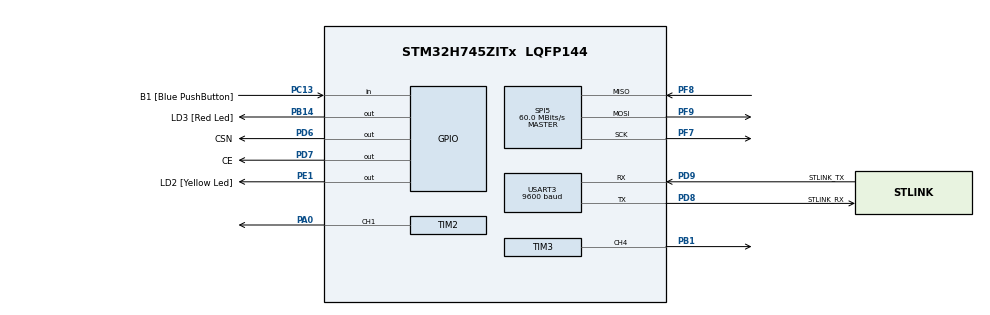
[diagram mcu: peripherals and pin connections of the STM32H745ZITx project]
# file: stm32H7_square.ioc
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CortexM4.IPs=BDMA,CORTEX_M4\:I,DEBUG,DMA,FATFS_M4\:I,FREERTOS_M4\:I,GPIO,IWDG2\:I,MDMA,NVIC2\:I,OPENAMP_M4\:I,PDM2PCM_M4\:I,PWR,RCC,RESMGR_UTILITY,SYS_M4\:I,USB_DEVICE_M4\:I,USB_HOST_M4\:I,VREFBUF,WWDG2\:I,USART3
CortexM4.Pins=PE1
CortexM7.IPs=BDMA\:I,CORTEX_M7\:I,DEBUG\:I,DMA\:I,FATFS_M7\:I,FREERTOS_M7\:I,GPIO\:I,IWDG1\:I,MDMA\:I,NVIC1\:I,OPENAMP_M7\:I,PDM2PCM_M7\:I,PWR\:I,RCC\:I,RESMGR_UTILITY\:I,SYS\:I,USB_DEVICE_M7\:I,USB_HOST_M7\:I,VREFBUF\:I,WWDG1\:I,USART3\:I,TIM2\:I,SPI5\:I,TIM3\:I
CortexM7.Pins=PC13
Mcu.Family=STM32H7
Mcu.Name=STM32H745ZITx
Mcu.Package=LQFP144
NVIC1.PriorityGroup=NVIC_PRIORITYGROUP_4
NVIC2.PriorityGroup=NVIC_PRIORITYGROUP_4
PA0.PinAttribute=CortexM7
PA0.Signal=S_TIM2_CH1_ETR
PB1.PinAttribute=CortexM7
PB1.Signal=S_TIM3_CH4
PB14.GPIO_Label=LD3 [Red Led]
PB14.PinAttribute=Free
PB14.Signal=GPIO_Output
PC12.PinAttribute=CortexM7
PC12.Signal=SPI3_MOSI
PC13.GPIO_Label=B1 [Blue PushButton]
PC13.PinAttribute=CortexM7
PC13.Signal=GPIO_Input
PC14-OSC32_IN\ (OSC32_IN).Mode=LSE-External-Oscillator
PC14-OSC32_IN\ (OSC32_IN).PinAttribute=CortexM7
PC14-OSC32_IN\ (OSC32_IN).Signal=RCC_OSC32_IN
PC15-OSC32_OUT\ (OSC32_OUT).Mode=LSE-External-Oscillator
PC15-OSC32_OUT\ (OSC32_OUT).PinAttribute=CortexM7
PC15-OSC32_OUT\ (OSC32_OUT).Signal=RCC_OSC32_OUT
PD6.GPIO_Label=CSN
PD6.PinAttribute=Free
PD6.Signal=GPIO_Output
PD7.GPIO_Label=CE
PD7.PinAttribute=Free
PD7.Signal=GPIO_Output
PD8.GPIO_Label=STLINK_RX
PD8.Mode=Asynchronous
PD8.PinAttribute=CortexM7
PD8.Signal=USART3_TX
PD9.GPIO_Label=STLINK_TX
PD9.Mode=Asynchronous
PD9.PinAttribute=CortexM7
PD9.Signal=USART3_RX
PE1.GPIO_Label=LD2 [Yellow Led]
PE1.PinAttribute=CortexM4
PE1.Signal=GPIO_Output
PF7.Mode=Full_Duplex_Master
PF7.PinAttribute=CortexM7
PF7.Signal=SPI5_SCK
PF8.Mode=Full_Duplex_Master
PF8.PinAttribute=CortexM7
PF8.Signal=SPI5_MISO
PF9.Mode=Full_Duplex_Master
PF9.PinAttribute=CortexM7
PF9.Signal=SPI5_MOSI
PH0-OSC_IN\ (PH0).Mode=HSE-External-Clock-Source
PH0-OSC_IN\ (PH0).PinAttribute=CortexM7
PH0-OSC_IN\ (PH0).Signal=RCC_OSC_IN
ProjectManager.HeapSize=M4-0x200,M7-0x200
ProjectManager.StackSize=M4-0x400,M7-0x400
ProjectManager.TargetToolchain=STM32CubeIDE
RCC.ADCFreq_Value=16125000
RCC.APB1Freq_Value=120000000
RCC.APB2Freq_Value=120000000
RCC.APB3Freq_Value=120000000
RCC.APB4Freq_Value=120000000
RCC.CortexFreq_Value=480000000
RCC.D1PPRE=RCC_APB3_DIV2
RCC.D2PPRE1=RCC_APB1_DIV2
RCC.D2PPRE2=RCC_APB2_DIV2
RCC.D3PPRE=RCC_APB4_DIV2
RCC.DIVM1=2
RCC.DIVN1=240
RCC.HCLKFreq_Value=240000000
RCC.HPRE=RCC_HCLK_DIV2
RCC.HSE_VALUE=8000000
RCC.PLLSourceVirtual=RCC_PLLSOURCE_HSE
RCC.SPI123CLockSelection=RCC_SPI123CLKSOURCE_CLKP
RCC.SYSCLKFreq_VALUE=480000000
RCC.SYSCLKSource=RCC_SYSCLKSOURCE_PLLCLK
RCC.USBFreq_Value=480000000
SH.S_TIM2_CH1_ETR.0=TIM2_CH1,PWM Generation1 CH1
SH.S_TIM3_CH4.0=TIM3_CH4,PWM Generation4 CH4
SPI5.CalculateBaudRate=60.0 MBits/s
SPI5.Direction=SPI_DIRECTION_2LINES
SPI5.Mode=SPI_MODE_MASTER
SPI5.VirtualType=VM_MASTER
TIM2.AutoReloadPreload=TIM_AUTORELOAD_PRELOAD_ENABLE
TIM2.Channel-PWM\ Generation1\ CH1=TIM_CHANNEL_1
TIM2.Period=63999
TIM2.Prescaler=74
TIM3.AutoReloadPreload=TIM_AUTORELOAD_PRELOAD_ENABLE
TIM3.Channel-PWM\ Generation4\ CH4=TIM_CHANNEL_4
TIM3.Period=63999
TIM3.Prescaler=74
USART3.BaudRate=9600
USART3.VirtualMode-Asynchronous=VM_ASYNC
VP_TIM2_VS_ClockSourceINT.Mode=Internal
VP_TIM3_VS_ClockSourceINT.Mode=Internal
board=custom

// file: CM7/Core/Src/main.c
/* USER CODE BEGIN Header */
/**
 ******************************************************************************
 * @file           : main.c
 * @brief          : Main program body
 ******************************************************************************
 * @attention
 *
 * Copyright (c) 2024 STMicroelectronics.
 * All rights reserved.
 *
 * This software is licensed under terms that can be found in the LICENSE file
 * in the root directory of this software component.
 * If no LICENSE file comes with this software, it is provided AS-IS.
 *
 ******************************************************************************
 */
/* USER CODE END Header */
#include "main.h"

/* USER CODE BEGIN Includes */
#include "MY_NRF24.h"
/* USER CODE END Includes */

/* USER CODE BEGIN PD */

#ifndef HSEM_ID_0
#define HSEM_ID_0 (0U) /* HW semaphore 0*/
#endif

#define Nrf_CE_Pin GPIO_PIN_6
#define Nrf_CE_GPIO_Port GPIOC
#define Nrf_CSn_Pin GPIO_PIN_7
#define Nrf_CSn_GPIO_Port GPIOC
/* USER CODE END PD */

SPI_HandleTypeDef hspi5;

TIM_HandleTypeDef htim2;
TIM_HandleTypeDef htim3;

UART_HandleTypeDef huart3;

void SystemClock_Config(void);
static void MX_GPIO_Init(void);
static void MX_USART3_UART_Init(void);
static void MX_TIM2_Init(void);
static void MX_SPI5_Init(void);
static void MX_TIM3_Init(void);

/* USER CODE BEGIN 0 */
uint64_t RxpipeAddrs = 0x11223344AA;
char myRxData[50];

//Control de giro servomotor ------------------------------------------------

void Rotate_Left() {
	__HAL_TIM_SET_COMPARE(&htim3, TIM_CHANNEL_4, (63999 * 0.05));
}

void Rotate_Center(void) {
	__HAL_TIM_SET_COMPARE(&htim3, TIM_CHANNEL_4, 63999 * 0.075);
}

void Rotate_Right(void) {
	__HAL_TIM_SET_COMPARE(&htim3, TIM_CHANNEL_4, (63999 * 0.1));
}

void rotate(uint32_t angle) {
	double val = (angle + 45) * 0.05 / 90 + 0.05;
	__HAL_TIM_SET_COMPARE(&htim3, TIM_CHANNEL_4, (63999 * val));
}

//-----------------------------------------------------------------------------------

//Control de potencia de traccion-----------------------------------------------------

void Forward(double power) { //POWER 50-100
	double val = 0.5f;
	uint32_t arg = 0;
	double speed = power * 0.025 / 100;
//	double speed = power * 0.05 / 100;
	HAL_Delay(2000);
	while (val * 100 < 101) { //Target : 0.1
		val = val + 0.01f;
		arg = (63999 * 0.075) + (63999 * speed * val);
//		arg = (63999 * 0.05) + (63999 * speed * val);
		__HAL_TIM_SET_COMPARE(&htim2, TIM_CHANNEL_1, arg);
		HAL_Delay(100);
	}
}

void Backward(double power) { //POWER 0-100
	double val = 0.5f;
	uint32_t arg = 0;
	double speed = power * 0.025 / 100;
	HAL_Delay(2000);
	while (val * 100 < 101) { //Target : 0.05
		val = val + 0.01f;
		arg = (63999 * 0.075) - (63999 * speed * val);
		__HAL_TIM_SET_COMPARE(&htim2, TIM_CHANNEL_1, arg);
		HAL_Delay(100);
	}
}

//----------------------------------------------------------------------------------------

void processCharacters(char *data) {
	int i = 0;
	char c;

	while ((c = data[i++]) != '\0') { // Recorre cada carácter hasta encontrar el caracter nulo '\0'
		switch (c) {
		case 'r':
			Rotate_Right();
			break;
		case 'l':
			Rotate_Left();
			break;
		case 'c':
			Rotate_Center();
			break;
		case 'f':
			Forward(70);
			break;
		case 'b':
			Backward(20);
			break;
		case '1':
			HAL_Delay(1000);
			break;
		default:
			// Opcional: Manejar caracteres no esperados o simplemente no hacer nada
			break;
		}
	}
}
/* USER CODE END 0 */

int main(void)
{
/* USER CODE BEGIN Boot_Mode_Sequence_0 */
	int32_t timeout;
/* USER CODE END Boot_Mode_Sequence_0 */

/* USER CODE BEGIN Boot_Mode_Sequence_1 */
	/* Wait until CPU2 boots and enters in stop mode or timeout*/
	timeout = 0xFFFF;
	while ((__HAL_RCC_GET_FLAG(RCC_FLAG_D2CKRDY) != RESET) && (timeout-- > 0))
		;
	if (timeout < 0) {
		Error_Handler();
	}
/* USER CODE END Boot_Mode_Sequence_1 */
  /* MCU Configuration--------------------------------------------------------*/

  /* Reset of all peripherals, Initializes the Flash interface and the Systick. */
  HAL_Init();

  /* Configure the system clock */
  SystemClock_Config();
/* USER CODE BEGIN Boot_Mode_Sequence_2 */
	/* When system initialization is finished, Cortex-M7 will release Cortex-M4 by means of
	 HSEM notification */
	/*HW semaphore Clock enable*/
	__HAL_RCC_HSEM_CLK_ENABLE();
	/*Take HSEM */
	HAL_HSEM_FastTake(HSEM_ID_0);
	/*Release HSEM in order to notify the CPU2(CM4)*/
	HAL_HSEM_Release(HSEM_ID_0, 0);
	/* wait until CPU2 wakes up from stop mode */
	timeout = 0xFFFF;
	while ((__HAL_RCC_GET_FLAG(RCC_FLAG_D2CKRDY) == RESET) && (timeout-- > 0))
		;
	if (timeout < 0) {
		Error_Handler();
	}
/* USER CODE END Boot_Mode_Sequence_2 */

  /* Initialize all configured peripherals */
  MX_GPIO_Init();
  MX_USART3_UART_Init();
  MX_TIM2_Init();
  MX_SPI5_Init();
  MX_TIM3_Init();
  /* USER CODE BEGIN 2 */
	HAL_TIM_PWM_Start(&htim2, TIM_CHANNEL_1);
	HAL_TIM_PWM_Start(&htim3, TIM_CHANNEL_4);
	//NO ACK
	NRF24_begin(GPIOC, Nrf_CSn_Pin, Nrf_CE_Pin, hspi5);
	nrf24_DebugUART_Init(huart3);
	NRF24_setAutoAck(false);
	NRF24_setChannel(52);
	NRF24_setPayloadSize(32);
	NRF24_setDataRate(RF24_2MBPS);
	NRF24_openReadingPipe(0, RxpipeAddrs);
	NRF24_enableDynamicPayloads();
	printRadioSettings();
	NRF24_startListening();
	printf("Empezando conexion\r\n");
  /* USER CODE END 2 */

  /* Infinite loop */
	while (1) {

    /* USER CODE BEGIN 3 */
		if (NRF24_available()) {
			NRF24_read(myRxData, 32);
			myRxData[32] = '\r';
			myRxData[32 + 1] = '\n';
			HAL_UART_Transmit(&huart3, (uint8_t*) myRxData, 32 + 2, 10);
		}

//		rotate(45);
//		HAL_Delay(500);
//		rotate(-45);
//		HAL_Delay(500);
//		rotate(0);
//		HAL_Delay(500);
//		rotate(25);.

//		HAL_Delay(500);
//		rotate(-25);
//		HAL_Delay(500);

//		Forward();
//		HAL_Delay(2000);
//		Backward();
//		HAL_Delay(2000);

	}

  /* USER CODE END 3 */
}

void SystemClock_Config(void)
{
  RCC_OscInitTypeDef RCC_OscInitStruct = {0};
  RCC_ClkInitTypeDef RCC_ClkInitStruct = {0};

  /** Supply configuration update enable
  */
  HAL_PWREx_ConfigSupply(PWR_DIRECT_SMPS_SUPPLY);

  /** Configure the main internal regulator output voltage
  */
  __HAL_PWR_VOLTAGESCALING_CONFIG(PWR_REGULATOR_VOLTAGE_SCALE2);

  while(!__HAL_PWR_GET_FLAG(PWR_FLAG_VOSRDY)) {}

  /** Initializes the RCC Oscillators according to the specified parameters
  * in the RCC_OscInitTypeDef structure.
  */
  RCC_OscInitStruct.OscillatorType = RCC_OSCILLATORTYPE_HSE;
  RCC_OscInitStruct.HSEState = RCC_HSE_BYPASS;
  RCC_OscInitStruct.PLL.PLLState = RCC_PLL_ON;
  RCC_OscInitStruct.PLL.PLLSource = RCC_PLLSOURCE_HSE;
  RCC_OscInitStruct.PLL.PLLM = 2;
  RCC_OscInitStruct.PLL.PLLN = 120;
  RCC_OscInitStruct.PLL.PLLP = 2;
  RCC_OscInitStruct.PLL.PLLQ = 2;
  RCC_OscInitStruct.PLL.PLLR = 2;
  RCC_OscInitStruct.PLL.PLLRGE = RCC_PLL1VCIRANGE_2;
  RCC_OscInitStruct.PLL.PLLVCOSEL = RCC_PLL1VCOWIDE;
  RCC_OscInitStruct.PLL.PLLFRACN = 0;
  if (HAL_RCC_OscConfig(&RCC_OscInitStruct) != HAL_OK)
  {
    Error_Handler();
  }

  /** Initializes the CPU, AHB and APB buses clocks
  */
  RCC_ClkInitStruct.ClockType = RCC_CLOCKTYPE_HCLK|RCC_CLOCKTYPE_SYSCLK
                              |RCC_CLOCKTYPE_PCLK1|RCC_CLOCKTYPE_PCLK2
                              |RCC_CLOCKTYPE_D3PCLK1|RCC_CLOCKTYPE_D1PCLK1;
  RCC_ClkInitStruct.SYSCLKSource = RCC_SYSCLKSOURCE_PLLCLK;
  RCC_ClkInitStruct.SYSCLKDivider = RCC_SYSCLK_DIV1;
  RCC_ClkInitStruct.AHBCLKDivider = RCC_HCLK_DIV2;
  RCC_ClkInitStruct.APB3CLKDivider = RCC_APB3_DIV2;
  RCC_ClkInitStruct.APB1CLKDivider = RCC_APB1_DIV2;
  RCC_ClkInitStruct.APB2CLKDivider = RCC_APB2_DIV2;
  RCC_ClkInitStruct.APB4CLKDivider = RCC_APB4_DIV2;

  if (HAL_RCC_ClockConfig(&RCC_ClkInitStruct, FLASH_LATENCY_2) != HAL_OK)
  {
    Error_Handler();
  }
}

static void MX_SPI5_Init(void)
{

  /* SPI5 parameter configuration*/
  hspi5.Instance = SPI5;
  hspi5.Init.Mode = SPI_MODE_MASTER;
  hspi5.Init.Direction = SPI_DIRECTION_2LINES;
  hspi5.Init.DataSize = SPI_DATASIZE_8BIT;
  hspi5.Init.CLKPolarity = SPI_POLARITY_LOW;
  hspi5.Init.CLKPhase = SPI_PHASE_1EDGE;
  hspi5.Init.NSS = SPI_NSS_SOFT;
  hspi5.Init.BaudRatePrescaler = SPI_BAUDRATEPRESCALER_16;
  hspi5.Init.FirstBit = SPI_FIRSTBIT_MSB;
  hspi5.Init.TIMode = SPI_TIMODE_DISABLE;
  hspi5.Init.CRCCalculation = SPI_CRCCALCULATION_DISABLE;
  hspi5.Init.CRCPolynomial = 0x0;
  hspi5.Init.NSSPMode = SPI_NSS_PULSE_ENABLE;
  hspi5.Init.NSSPolarity = SPI_NSS_POLARITY_LOW;
  hspi5.Init.FifoThreshold = SPI_FIFO_THRESHOLD_01DATA;
  hspi5.Init.TxCRCInitializationPattern = SPI_CRC_INITIALIZATION_ALL_ZERO_PATTERN;
  hspi5.Init.RxCRCInitializationPattern = SPI_CRC_INITIALIZATION_ALL_ZERO_PATTERN;
  hspi5.Init.MasterSSIdleness = SPI_MASTER_SS_IDLENESS_00CYCLE;
  hspi5.Init.MasterInterDataIdleness = SPI_MASTER_INTERDATA_IDLENESS_00CYCLE;
  hspi5.Init.MasterReceiverAutoSusp = SPI_MASTER_RX_AUTOSUSP_DISABLE;
  hspi5.Init.MasterKeepIOState = SPI_MASTER_KEEP_IO_STATE_DISABLE;
  hspi5.Init.IOSwap = SPI_IO_SWAP_DISABLE;
  if (HAL_SPI_Init(&hspi5) != HAL_OK)
  {
    Error_Handler();
  }

}

static void MX_TIM2_Init(void)
{

  TIM_ClockConfigTypeDef sClockSourceConfig = {0};
  TIM_MasterConfigTypeDef sMasterConfig = {0};
  TIM_OC_InitTypeDef sConfigOC = {0};

  htim2.Instance = TIM2;
  htim2.Init.Prescaler = 74;
  htim2.Init.CounterMode = TIM_COUNTERMODE_UP;
  htim2.Init.Period = 63999;
  htim2.Init.ClockDivision = TIM_CLOCKDIVISION_DIV1;
  htim2.Init.AutoReloadPreload = TIM_AUTORELOAD_PRELOAD_ENABLE;
  if (HAL_TIM_Base_Init(&htim2) != HAL_OK)
  {
    Error_Handler();
  }
  sClockSourceConfig.ClockSource = TIM_CLOCKSOURCE_INTERNAL;
  if (HAL_TIM_ConfigClockSource(&htim2, &sClockSourceConfig) != HAL_OK)
  {
    Error_Handler();
  }
  if (HAL_TIM_PWM_Init(&htim2) != HAL_OK)
  {
    Error_Handler();
  }
  sMasterConfig.MasterOutputTrigger = TIM_TRGO_RESET;
  sMasterConfig.MasterSlaveMode = TIM_MASTERSLAVEMODE_DISABLE;
  if (HAL_TIMEx_MasterConfigSynchronization(&htim2, &sMasterConfig) != HAL_OK)
  {
    Error_Handler();
  }
  sConfigOC.OCMode = TIM_OCMODE_PWM1;
  sConfigOC.Pulse = 0;
  sConfigOC.OCPolarity = TIM_OCPOLARITY_HIGH;
  sConfigOC.OCFastMode = TIM_OCFAST_DISABLE;
  if (HAL_TIM_PWM_ConfigChannel(&htim2, &sConfigOC, TIM_CHANNEL_1) != HAL_OK)
  {
    Error_Handler();
  }
  HAL_TIM_MspPostInit(&htim2);

}

static void MX_TIM3_Init(void)
{

  TIM_ClockConfigTypeDef sClockSourceConfig = {0};
  TIM_MasterConfigTypeDef sMasterConfig = {0};
  TIM_OC_InitTypeDef sConfigOC = {0};

  htim3.Instance = TIM3;
  htim3.Init.Prescaler = 74;
  htim3.Init.CounterMode = TIM_COUNTERMODE_UP;
  htim3.Init.Period = 63999;
  htim3.Init.ClockDivision = TIM_CLOCKDIVISION_DIV1;
  htim3.Init.AutoReloadPreload = TIM_AUTORELOAD_PRELOAD_ENABLE;
  if (HAL_TIM_Base_Init(&htim3) != HAL_OK)
  {
    Error_Handler();
  }
  sClockSourceConfig.ClockSource = TIM_CLOCKSOURCE_INTERNAL;
  if (HAL_TIM_ConfigClockSource(&htim3, &sClockSourceConfig) != HAL_OK)
  {
    Error_Handler();
  }
  if (HAL_TIM_PWM_Init(&htim3) != HAL_OK)
  {
    Error_Handler();
  }
  sMasterConfig.MasterOutputTrigger = TIM_TRGO_RESET;
  sMasterConfig.MasterSlaveMode = TIM_MASTERSLAVEMODE_DISABLE;
  if (HAL_TIMEx_MasterConfigSynchronization(&htim3, &sMasterConfig) != HAL_OK)
  {
    Error_Handler();
  }
  sConfigOC.OCMode = TIM_OCMODE_PWM1;
  sConfigOC.Pulse = 0;
  sConfigOC.OCPolarity = TIM_OCPOLARITY_HIGH;
  sConfigOC.OCFastMode = TIM_OCFAST_DISABLE;
  if (HAL_TIM_PWM_ConfigChannel(&htim3, &sConfigOC, TIM_CHANNEL_4) != HAL_OK)
  {
    Error_Handler();
  }
  HAL_TIM_MspPostInit(&htim3);

}

static void MX_USART3_UART_Init(void)
{

  huart3.Instance = USART3;
  huart3.Init.BaudRate = 9600;
  huart3.Init.WordLength = UART_WORDLENGTH_8B;
  huart3.Init.StopBits = UART_STOPBITS_1;
  huart3.Init.Parity = UART_PARITY_NONE;
  huart3.Init.Mode = UART_MODE_TX_RX;
  huart3.Init.HwFlowCtl = UART_HWCONTROL_NONE;
  huart3.Init.OverSampling = UART_OVERSAMPLING_16;
  huart3.Init.OneBitSampling = UART_ONE_BIT_SAMPLE_DISABLE;
  huart3.Init.ClockPrescaler = UART_PRESCALER_DIV1;
  huart3.AdvancedInit.AdvFeatureInit = UART_ADVFEATURE_NO_INIT;
  if (HAL_UART_Init(&huart3) != HAL_OK)
  {
    Error_Handler();
  }
  if (HAL_UARTEx_SetTxFifoThreshold(&huart3, UART_TXFIFO_THRESHOLD_1_8) != HAL_OK)
  {
    Error_Handler();
  }
  if (HAL_UARTEx_SetRxFifoThreshold(&huart3, UART_RXFIFO_THRESHOLD_1_8) != HAL_OK)
  {
    Error_Handler();
  }
  if (HAL_UARTEx_DisableFifoMode(&huart3) != HAL_OK)
  {
    Error_Handler();
  }

}

static void MX_GPIO_Init(void)
{
  GPIO_InitTypeDef GPIO_InitStruct = {0};

  /* GPIO Ports Clock Enable */
  __HAL_RCC_GPIOC_CLK_ENABLE();
  __HAL_RCC_GPIOF_CLK_ENABLE();
  __HAL_RCC_GPIOH_CLK_ENABLE();
  __HAL_RCC_GPIOA_CLK_ENABLE();
  __HAL_RCC_GPIOB_CLK_ENABLE();
  __HAL_RCC_GPIOD_CLK_ENABLE();

  /*Configure GPIO pin Output Level */
  HAL_GPIO_WritePin(GPIOC, Nrf_CE_Pin|Nrf_CSn_Pin, GPIO_PIN_RESET);

  /*Configure GPIO pin : B1_Pin */
  GPIO_InitStruct.Pin = B1_Pin;
  GPIO_InitStruct.Mode = GPIO_MODE_INPUT;
  GPIO_InitStruct.Pull = GPIO_NOPULL;
  HAL_GPIO_Init(B1_GPIO_Port, &GPIO_InitStruct);

  /*Configure GPIO pins : Nrf_CE_Pin Nrf_CSn_Pin */
  GPIO_InitStruct.Pin = Nrf_CE_Pin|Nrf_CSn_Pin;
  GPIO_InitStruct.Mode = GPIO_MODE_OUTPUT_PP;
  GPIO_InitStruct.Pull = GPIO_NOPULL;
  GPIO_InitStruct.Speed = GPIO_SPEED_FREQ_LOW;
  HAL_GPIO_Init(GPIOC, &GPIO_InitStruct);

}

void Error_Handler(void)
{
	__disable_irq();
	while (1) {
	}
}
